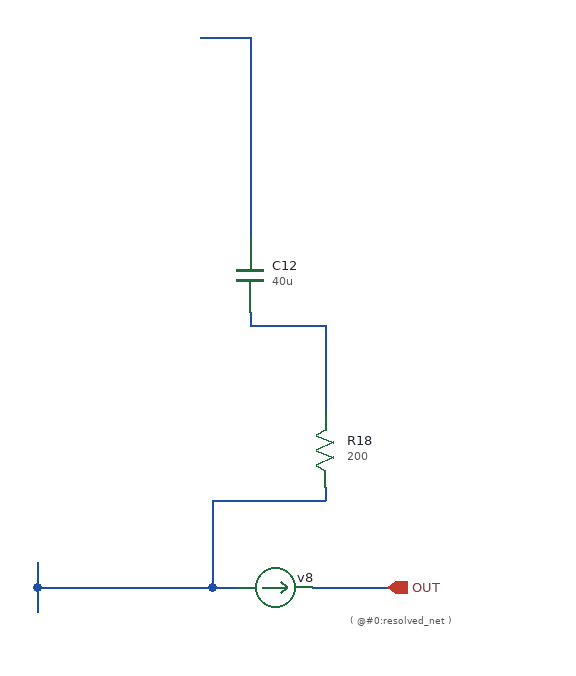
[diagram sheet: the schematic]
v {xschem version=3.4.8RC file_version=1.3}
G {}
K {}
V {}
S {}
F {}
E {}
T {( @#0:resolved_net )} -300 155 0 1 0.2 0.2 {name=p5 layer=15}
N -550 140 -550 160 {lab=#net1}
N -550 120 -550 140 {lab=#net1}
N -330 140 -270 140 {lab=OUT}
N -550 140 -410 140 {lab=#net1}
N -410 140 -390 140 {lab=#net1}
N -320 -70 -320 0 {lab=#net2}
N -380 -300 -380 -140 {lab=#net3}
N -380 -70 -320 -70 {lab=#net2}
N -380 -80 -380 -70 {lab=#net2}
N -420 -300 -380 -300 {lab=#net3}
N -320 60 -320 70 {lab=#net1}
N -410 70 -410 140 {lab=#net1}
N -410 70 -320 70 {lab=#net1}
C {devices/capa} -380 -110 0 0 {name=C12 m=1 value="40u"}
C {devices/res} -320 30 0 1 {name=R18 m=1 value=200}
C {devices/ammeter} -360 140 3 0 {name=v8}
C {devices/opin} -270 140 0 0 {name=p5 lab=OUT}
